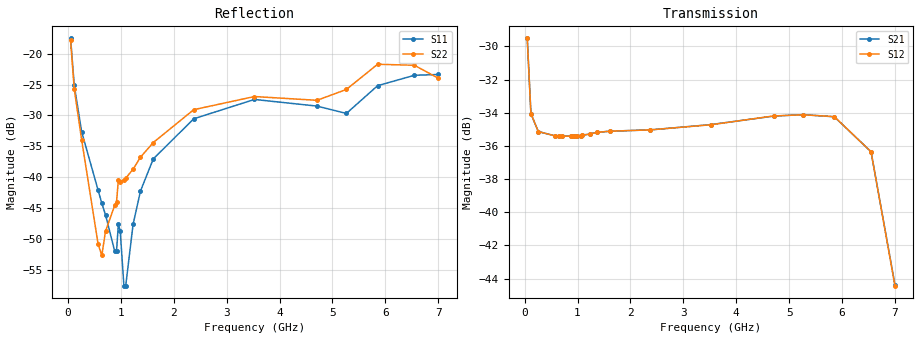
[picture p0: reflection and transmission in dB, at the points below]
! Integrated Device Technology
! Corporate Headquarters
! 6024 Silver Creek Valley Road
! San Jose, CA 95138  USA
! Phone:  1-408-284-8200
! Toll Free:  1-800-223-1366
! Webpage:  http://www.idt.com/
! Timing and RF Division
! 515 Groton Road, Suite 102
! Westford, MA 01886-6024
! Device:  F2258
! Description: Voltage Variable RF Attenuator
! Frequency:  50.0 -  6000.00 MHz
! Package:  3x3 mm Thin QFN Plastic Package: 16 pin
! Ports:  2 RF, 2 DC
!  Pin  1  = NC
!  Pin  2  = NC
!  Pin  3  = RF2  = Port 2
!  Pin  4  = GND
!  Pin  5  = Vdd
!  Pin  6  = NC
!  Pin  7  = VCTRL
!  Pin  8  = NC
!  Pin  9  = GND
!  Pin 10  = RF1  = Port 1
!  Pin 11  = NC
!  Pin 12  = NC
!  Pin 13  = NC
!  Pin 14  = NC
!  Pin 15  = NC
!  Pin 16  = NC
! Vcntrl:  2.240 Volts
! Vdd:  +3.300 Volts
! Current:  1.149 mA
! Data:  The device was measured on a the F2258 evaluation board which has
!  individual transmission lines to the RF pins.  Data was collected
!  using a calibrated network analyzer.  The evaluation board was
!  de-embedded using a TRL calibration technique.
!  The reference plane is the edge of the package pin.
! Misc:  SN 10
!  Action Tracker AT0285
! Date Measured:  2014-12-10
! Date:  2016-01-13  MJV
! Note:
!  Integrated Device Technology supplies this data as a sample of measured
!  data at the package pin for this product.  Your particular data for this
!  product may vary.
!  Data was taken at 25 degrees C.
!  Integrated Device Technology reserves the right to change this data at anytime.
!Freq_(GHz)  S11M_(dB)  S11P_(deg)  S21M_(dB)  S21P_(deg)  S12M_(dB)  S12P_(deg)  S22M_(dB)  S22P_(deg)
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# GHz S dB R 50
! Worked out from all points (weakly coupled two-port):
!   201 points, 50 MHz to 7 GHz, reference 50 ohm
!   highest |S21| = -29.51 dB at 50 MHz (marker M1); lowest = -44.4 dB at 7 GHz (marker M2)
!   lowest |S11| = -57.5 dB at 1.093 GHz (marker M3), VSWR 1.00, Z = 49.9 + j0.115 ohm
!   |S11| at or under -10 dB: start of sweep to end of sweep
!   |S22| runs from -52.6 to -17.9 dB; largest |S21 - S12| = 7.2e-05
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0.05  -17.55 -111.0  -29.51 -68.3  -29.51 -68.3  -17.89 -111.1
0.1195  -25.12 -106.9  -34.05 -36.8  -34.05 -36.8  -25.73 -106.2
0.2585  -32.61 -111.8  -35.13 -18.8  -35.13 -18.8  -33.89 -110.8
0.57125  -42.08 -124.7  -35.39 -10.4  -35.39 -10.4  -50.81 -157.2
0.64075  -44.19 -128.0  -35.41 -9.7  -35.40 -9.7  -52.58 165.5
0.71025  -46.03 -137.8  -35.40 -9.2  -35.41 -9.2  -48.67 126.1
0.884  -51.90 165.7  -35.40 -8.4  -35.41 -8.4  -44.51 110.8
0.91875  -51.85 150.0  -35.40 -8.4  -35.40 -8.3  -43.95 108.8
0.9535  -47.53 -162.9  -35.41 -8.2  -35.41 -8.2  -40.37 118.1
0.98825  -48.63 -174.5  -35.40 -8.1  -35.39 -8.1  -40.69 115.6
1.05775  -57.45 154.8  -35.37 -8.0  -35.37 -8.0  -40.37 100.4
1.0925  -57.47 120.7  -35.35 -7.9  -35.35 -7.9  -40.12 96.3
1.2315  -47.56 47.0  -35.28 -8.0  -35.28 -7.9  -38.67 74.9
1.3705  -42.21 37.0  -35.18 -8.4  -35.18 -8.4  -36.74 63.2
1.61375  -37.00 33.0  -35.11 -9.6  -35.11 -9.6  -34.36 50.8
2.37825  -30.53 48.2  -35.03 -13.2  -35.03 -13.3  -29.06 42.0
3.525  -27.41 91.6  -34.71 -19.7  -34.72 -19.7  -26.94 66.5
4.7065  -28.48 95.7  -34.20 -28.9  -34.19 -28.8  -27.55 57.8
5.2625  -29.67 54.3  -34.11 -34.9  -34.12 -35.0  -25.80 20.4
5.85325  -25.19 29.8  -34.24 -45.5  -34.23 -45.5  -21.73 -3.0
6.54825  -23.51 45.0  -36.35 -66.4  -36.35 -66.3  -21.89 -38.1
7  -23.38 84.4  -44.37 -62.0  -44.43 -61.4  -23.98 -129.8
